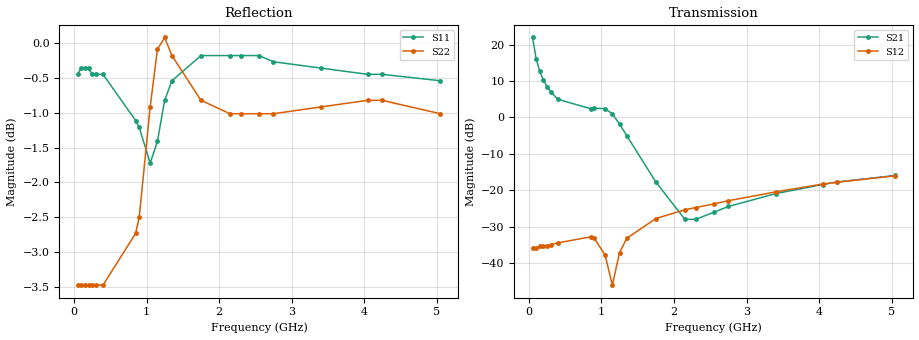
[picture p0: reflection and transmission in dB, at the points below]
!AT-36408
!S-PARAMETERS at Vce=3.6 V  Ic=100 mA.  LAST UPDATED 08-05-96
# ghz s ma r 50
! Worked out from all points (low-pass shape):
!   101 points, 50 MHz to 5.05 GHz, reference 50 ohm
!   highest |S21| = 21.97 dB at 50 MHz (marker M1); lowest = -28.0 dB at 2.3 GHz (marker M2)
!   |S21| within 3 dB of the highest: start of sweep to 75.41 MHz
!   lowest |S11| = -1.7 dB at 1.05 GHz (marker M3), VSWR 10.11, Z = 4.97 + j3.46 ohm
!   |S11| at or under -10 dB: nowhere
!   |S22| runs from -3.5 to 0.1 dB; largest |S21 - S12| = 13
!   S11 on the Smith chart (normalised r, x): 50 MHz: 0.03, -0.06; 850 MHz: 0.06, +0.10; 2.75 GHz: 0.02, +0.26; 4.05 GHz: 0.03, +0.44; 5.05 GHz: 0.04, +0.66
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0.05  0.95 -173.0  12.55 93.0  0.016 9.0  0.67 -165.0
0.1  0.96 -177.0  6.36 88.0  0.016 9.0  0.67 -172.0
0.15  0.96 -180.0  4.28 84.0  0.017 11.0  0.67 -174.0
0.2  0.96 179.0  3.25 80.0  0.017 13.0  0.67 -174.0
0.25  0.95 178.0  2.64 77.0  0.017 15.0  0.67 -174.0
0.3  0.95 177.0  2.24 74.0  0.018 16.0  0.67 -174.0
0.4  0.95 175.0  1.77 68.0  0.019 19.0  0.67 -173.0
0.85  0.88 169.0  1.32 27.0  0.023 6.0  0.73 -162.0
0.9  0.87 169.0  1.34 19.0  0.022 -1.0  0.75 -161.0
1.05  0.82 172.0  1.32 -15.0  0.013 -39.0  0.9 -160.0
1.15  0.85 175.0  1.12 -42.0  0.005 -138.0  0.99 -165.0
1.25  0.91 175.0  0.81 -66.0  0.014 140.0  1.01 -171.0
1.35  0.94 173.0  0.56 -84.0  0.022 118.0  0.98 -174.0
1.75  0.98 165.0  0.13 -126.0  0.041 90.0  0.91 -178.0
2.15  0.98 159.0  0.04 171.0  0.054 82.0  0.89 -178.0
2.3  0.98 157.0  0.04 138.0  0.058 80.0  0.89 -178.0
2.55  0.98 154.0  0.05 104.0  0.065 78.0  0.89 -178.0
2.75  0.97 151.0  0.06 91.0  0.072 76.0  0.89 -178.0
3.4  0.96 142.0  0.09 73.0  0.095 71.0  0.9 -180.0
4.05  0.95 132.0  0.12 63.0  0.122 62.0  0.91 176.0
4.25  0.95 129.0  0.13 60.0  0.129 59.0  0.91 175.0
5.05  0.94 113.0  0.16 48.0  0.158 49.0  0.89 168.0
